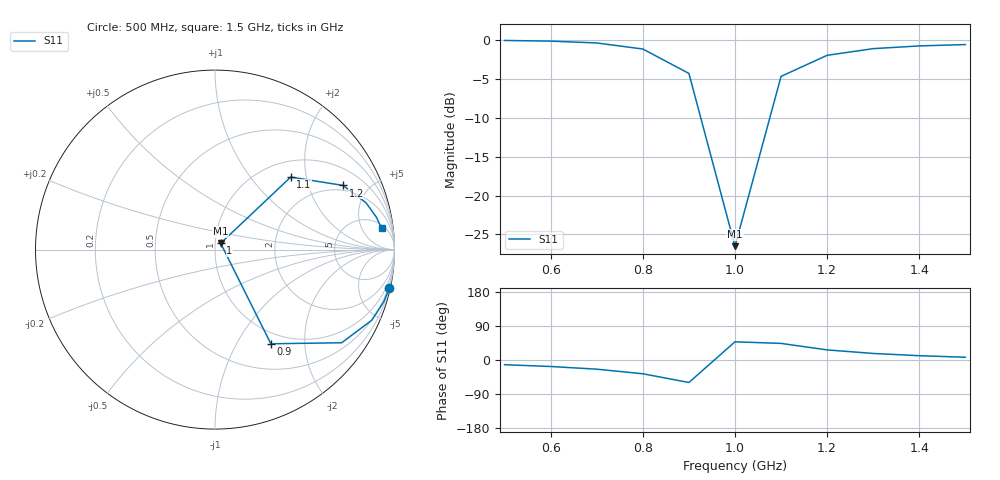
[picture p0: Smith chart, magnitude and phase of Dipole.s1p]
! Generated by circuitRF - EM: openEMS
! circuitRF-EM setup: Dipole ReferenceGrid
! circuitRF-EM layout: Dipole.c3d
! circuitRF-EM written: 2026-10-18 16:59:53Z
! circuitRF-EM geometry: 69ee941c6fe54ec2
! circuitRF-EM mesh: 70a78813e11eb097
! circuitRF-EM ports: b2d3c631ea696268
! circuitRF-EM model: openEMS 0.37.0 (v0.37.0, CSXCAD v0.7.0)
! circuitRF-EM port 1: 'port/1' from 'armLo' to 'armHi', lumped, 50 Ohm
! circuitRF-EM 3D grid: 114 x 115 x 116 = 1520760 cells; smallest cell 2.2766 mm on z, set by 'OpenEms.GridLines' given line at z = -82.7234 mm
! circuitRF-EM 3D openEMS run port 1: dt 4.65744E-12 s (estimate 4.65744E-12 s), 2686 steps, port signals 20.7 dB and energy 47.6 dB against 40 dB, stopped by openEMS's energy criterion, converged
! circuitRF-EM 3D dielectric loss fitted at: 1 GHz
! circuitRF-EM 3D perfect conductors: armLo, armHi
! circuitRF-EM 3D operating temperature: 20 C
! circuitRF-EM: re-running the EM setup rewrites this file. If circuitRF reports it as stale, the layout's cross-section changed after this file was written.
# GHz S RI R 50
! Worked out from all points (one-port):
!   11 points, 500 MHz to 1.5 GHz, reference 50 ohm
!   lowest |S11| = -26.5 dB at 1 GHz (marker M1), VSWR 1.10, Z = 53.1 + j3.74 ohm
!   |S11| at or under -10 dB: 925.7 MHz to 1.076 GHz (149.9 MHz wide, 15 % of centre)
!   S11 on the Smith chart (normalised r, x): 500 MHz: 0.24, -9.17; 900 MHz: 0.84, -1.40; 1 GHz: 1.06, +0.07; 1.1 GHz: 1.32, +1.62; 1.2 GHz: 1.73, +3.40; 1.5 GHz: 7, +12
0.5  0.9709 -0.2142
0.6  0.9406 -0.2903
0.7  0.8737 -0.3933
0.8  0.7056 -0.5191
0.9  0.3111 -0.5246
1  0.0316 0.0351
1.1  0.4218 0.4041
1.2  0.7132 0.3576
1.3  0.841 0.2614
1.4  0.8992 0.1806
1.5  0.9282 0.1181
